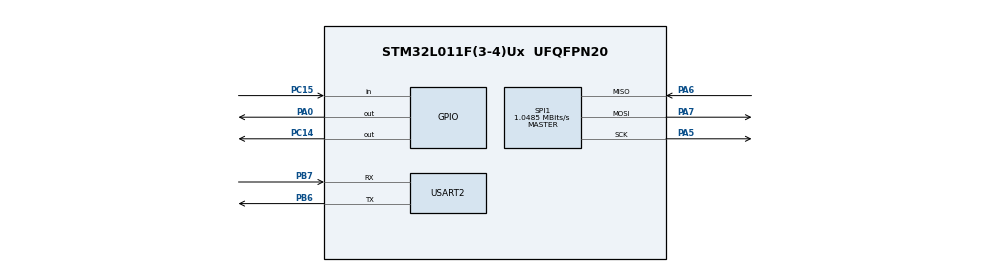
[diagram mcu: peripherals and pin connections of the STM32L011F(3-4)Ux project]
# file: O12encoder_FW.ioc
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Dma.Request0=USART2_TX
Dma.USART2_TX.0.Direction=DMA_MEMORY_TO_PERIPH
Dma.USART2_TX.0.Instance=DMA1_Channel2
Dma.USART2_TX.0.MemDataAlignment=DMA_MDATAALIGN_BYTE
Dma.USART2_TX.0.MemInc=DMA_MINC_ENABLE
Dma.USART2_TX.0.Mode=DMA_NORMAL
Dma.USART2_TX.0.PeriphDataAlignment=DMA_PDATAALIGN_BYTE
Dma.USART2_TX.0.PeriphInc=DMA_PINC_DISABLE
Dma.USART2_TX.0.Priority=DMA_PRIORITY_LOW
Mcu.Family=STM32L0
Mcu.Name=STM32L011F(3-4)Ux
Mcu.Package=UFQFPN20
NVIC.DMA1_Channel2_3_IRQn=true\:0\:0\:false\:false\:true\:false\:true\:true
NVIC.USART2_IRQn=true\:0\:0\:false\:false\:true\:true\:true\:true
PA0-CK_IN.Signal=GPIO_Output
PA13.Mode=Serial_Wire
PA13.Signal=SYS_SWDIO
PA14.Mode=Serial_Wire
PA14.Signal=SYS_SWCLK
PA5.Mode=Full_Duplex_Master
PA5.Signal=SPI1_SCK
PA6.Mode=Full_Duplex_Master
PA6.Signal=SPI1_MISO
PA7.Mode=Full_Duplex_Master
PA7.Signal=SPI1_MOSI
PB6.GPIO_PuPd=GPIO_PULLUP
PB6.Mode=Asynchronous
PB6.Signal=USART2_TX
PB7.GPIO_PuPd=GPIO_PULLUP
PB7.Mode=Asynchronous
PB7.Signal=USART2_RX
PC14-OSC32_IN.Signal=GPIO_Output
PC15-OSC32_OUT.Signal=GPIO_Input
ProjectManager.HeapSize=0x200
ProjectManager.StackSize=0x400
ProjectManager.TargetToolchain=STM32CubeIDE
RCC.AHBFreq_Value=2097000
RCC.APB1Freq_Value=2097000
RCC.APB1TimFreq_Value=2097000
RCC.APB2Freq_Value=2097000
RCC.APB2TimFreq_Value=2097000
RCC.HSE_VALUE=8000000
RCC.HSI16_VALUE=16000000
RCC.HSI_VALUE=16000000
RCC.LSE_VALUE=32768
RCC.MSI_VALUE=2097000
RCC.SYSCLKFreq_VALUE=2097000
RCC.VCOOutputFreq_Value=48000000
SPI1.CalculateBaudRate=1.0485 MBits/s
SPI1.Direction=SPI_DIRECTION_2LINES
SPI1.Mode=SPI_MODE_MASTER
SPI1.VirtualType=VM_MASTER
USART2.VirtualMode-Asynchronous=VM_ASYNC
board=custom

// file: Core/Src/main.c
/* USER CODE BEGIN Header */
/**
 ******************************************************************************
 * @file           : main.c
 * @brief          : Main program body
 ******************************************************************************
 * @attention
 *
 * Copyright (c) 2024 STMicroelectronics.
 * All rights reserved.
 *
 * This software is licensed under terms that can be found in the LICENSE file
 * in the root directory of this software component.
 * If no LICENSE file comes with this software, it is provided AS-IS.
 *
 ******************************************************************************
 */
/* USER CODE END Header */
#include "main.h"

/* USER CODE BEGIN Includes */

#include "comdef.h"
#include "utils.h"

/* USER CODE END Includes */

/* USER CODE BEGIN PD */

#define UART_TX_SIZE 10
#define UART_RX_SIZE 3

/* USER CODE END PD */

SPI_HandleTypeDef hspi1;

UART_HandleTypeDef huart2;
DMA_HandleTypeDef hdma_usart2_tx;

void SystemClock_Config(void);
static void MX_GPIO_Init(void);
static void MX_DMA_Init(void);
static void MX_USART2_UART_Init(void);
static void MX_SPI1_Init(void);

/* USER CODE BEGIN 0 */
static uint8_t uart_TX[UART_TX_SIZE] = {0};
static uint8_t uart_RX[UART_RX_SIZE] = {0};
static uint8_t uart_received_flag = 0;

/* USER CODE END 0 */

int main(void) {

    /* MCU Configuration--------------------------------------------------------*/

    /* Reset of all peripherals, Initializes the Flash interface and the Systick. */
    HAL_Init();

    /* Configure the system clock */
    SystemClock_Config();

    /* Initialize all configured peripherals */
    MX_GPIO_Init();
    MX_DMA_Init();
    MX_USART2_UART_Init();
    MX_SPI1_Init();
    /* USER CODE BEGIN 2 */

    static uint8_t spi_TX[2] = {0};
    static uint8_t spi_RX[2] = {0};

    static uint16_t m_angle = 0;
    static uint16_t m_angle_prev;
    static int32_t revs = 0;
    static int32_t cont_angle = 0;

    static int16_t encoder_res = 7;

    static uint16_t uart_cmd[3] = {0};

    HAL_GPIO_WritePin(GPIOA, GPIO_PIN_0, 1);

    /* USER CODE END 2 */

    /* Infinite loop */
    /* USER CODE BEGIN WHILE */
    while (1) {

        HAL_GPIO_WritePin(GPIOA, GPIO_PIN_0, 0);
        HAL_SPI_TransmitReceive(&hspi1, spi_TX, spi_RX, 2, HAL_MAX_DELAY);
        HAL_GPIO_WritePin(GPIOA, GPIO_PIN_0, 1);

        // angles represented in [0,32767] (~91 per degree)
        m_angle = ((uint16_t)(spi_RX[0]) << 8) + spi_RX[1] + 16384;

        if (m_angle_prev < 8192 && m_angle > 24576) { // detect angle wraparound and increment a revolution
            revs -= 32768;
        } else if (m_angle < 8192 && m_angle_prev > 24576) {
            revs += 32768;
        }
        cont_angle = m_angle + revs;
        m_angle_prev = m_angle;

        HAL_Delay(10);

        // if (uart_received_flag) {
        if (1) {
            uart_received_flag = 0;

            uart_cmd[0] = uart_RX[0] & CMD_MASK;
            uart_cmd[1] = (uart_RX[1] << 7) | (uart_RX[2]);
            uart_cmd[1] = pad14(uart_cmd[1]);

            if (uart_cmd[0] == CMD_GET_POSITION) {
                encoder_res = uart_cmd[1];
            }

            uart_TX[0] = (uint8_t)(cont_angle >> (encoder_res + 7)) & 0b01111111;
            uart_TX[1] = (uint8_t)(cont_angle >> (encoder_res + 0)) & 0b01111111;
            uart_TX[2] = MIN_INT8;

            HAL_GPIO_WritePin(GPIOC, GPIO_PIN_14, 1); // enable TX
            HAL_UART_Transmit_DMA(&huart2, uart_TX, 3);
        }

        /* USER CODE END WHILE */

    }
}

void SystemClock_Config(void) {
    RCC_OscInitTypeDef RCC_OscInitStruct = {0};
    RCC_ClkInitTypeDef RCC_ClkInitStruct = {0};
    RCC_PeriphCLKInitTypeDef PeriphClkInit = {0};

    /** Configure the main internal regulator output voltage
     */
    __HAL_PWR_VOLTAGESCALING_CONFIG(PWR_REGULATOR_VOLTAGE_SCALE1);

    /** Initializes the RCC Oscillators according to the specified parameters
     * in the RCC_OscInitTypeDef structure.
     */
    RCC_OscInitStruct.OscillatorType = RCC_OSCILLATORTYPE_HSI;
    RCC_OscInitStruct.HSIState = RCC_HSI_ON;
    RCC_OscInitStruct.HSICalibrationValue = RCC_HSICALIBRATION_DEFAULT;
    RCC_OscInitStruct.PLL.PLLState = RCC_PLL_ON;
    RCC_OscInitStruct.PLL.PLLSource = RCC_PLLSOURCE_HSI;
    RCC_OscInitStruct.PLL.PLLMUL = RCC_PLLMUL_4;
    RCC_OscInitStruct.PLL.PLLDIV = RCC_PLLDIV_2;
    if (HAL_RCC_OscConfig(&RCC_OscInitStruct) != HAL_OK) {
        Error_Handler();
    }

    /** Initializes the CPU, AHB and APB buses clocks
     */
    RCC_ClkInitStruct.ClockType = RCC_CLOCKTYPE_HCLK | RCC_CLOCKTYPE_SYSCLK | RCC_CLOCKTYPE_PCLK1 | RCC_CLOCKTYPE_PCLK2;
    RCC_ClkInitStruct.SYSCLKSource = RCC_SYSCLKSOURCE_PLLCLK;
    RCC_ClkInitStruct.AHBCLKDivider = RCC_SYSCLK_DIV1;
    RCC_ClkInitStruct.APB1CLKDivider = RCC_HCLK_DIV1;
    RCC_ClkInitStruct.APB2CLKDivider = RCC_HCLK_DIV1;

    if (HAL_RCC_ClockConfig(&RCC_ClkInitStruct, FLASH_LATENCY_1) != HAL_OK) {
        Error_Handler();
    }
    PeriphClkInit.PeriphClockSelection = RCC_PERIPHCLK_USART2;
    PeriphClkInit.Usart2ClockSelection = RCC_USART2CLKSOURCE_SYSCLK;
    if (HAL_RCCEx_PeriphCLKConfig(&PeriphClkInit) != HAL_OK) {
        Error_Handler();
    }
}

static void MX_SPI1_Init(void) {

    /* SPI1 parameter configuration*/
    hspi1.Instance = SPI1;
    hspi1.Init.Mode = SPI_MODE_MASTER;
    hspi1.Init.Direction = SPI_DIRECTION_2LINES;
    hspi1.Init.DataSize = SPI_DATASIZE_8BIT;
    hspi1.Init.CLKPolarity = SPI_POLARITY_LOW;
    hspi1.Init.CLKPhase = SPI_PHASE_1EDGE;
    hspi1.Init.NSS = SPI_NSS_SOFT;
    hspi1.Init.BaudRatePrescaler = SPI_BAUDRATEPRESCALER_2;
    hspi1.Init.FirstBit = SPI_FIRSTBIT_MSB;
    hspi1.Init.TIMode = SPI_TIMODE_DISABLE;
    hspi1.Init.CRCCalculation = SPI_CRCCALCULATION_DISABLE;
    hspi1.Init.CRCPolynomial = 7;
    if (HAL_SPI_Init(&hspi1) != HAL_OK) {
        Error_Handler();
    }
}

static void MX_USART2_UART_Init(void) {

    huart2.Instance = USART2;
    huart2.Init.BaudRate = 115200;
    huart2.Init.WordLength = UART_WORDLENGTH_8B;
    huart2.Init.StopBits = UART_STOPBITS_1;
    huart2.Init.Parity = UART_PARITY_NONE;
    huart2.Init.Mode = UART_MODE_TX_RX;
    huart2.Init.HwFlowCtl = UART_HWCONTROL_NONE;
    huart2.Init.OverSampling = UART_OVERSAMPLING_16;
    huart2.Init.OneBitSampling = UART_ONE_BIT_SAMPLE_DISABLE;
    huart2.AdvancedInit.AdvFeatureInit = UART_ADVFEATURE_NO_INIT;
    if (HAL_UART_Init(&huart2) != HAL_OK) {
        Error_Handler();
    }
}

static void MX_DMA_Init(void) {

    /* DMA controller clock enable */
    __HAL_RCC_DMA1_CLK_ENABLE();

    /* DMA interrupt init */
    /* DMA1_Channel2_3_IRQn interrupt configuration */
    HAL_NVIC_SetPriority(DMA1_Channel2_3_IRQn, 0, 0);
    HAL_NVIC_EnableIRQ(DMA1_Channel2_3_IRQn);
}

static void MX_GPIO_Init(void) {
    GPIO_InitTypeDef GPIO_InitStruct = {0};

    /* GPIO Ports Clock Enable */
    __HAL_RCC_GPIOC_CLK_ENABLE();
    __HAL_RCC_GPIOA_CLK_ENABLE();
    __HAL_RCC_GPIOB_CLK_ENABLE();

    /*Configure GPIO pin Output Level */
    HAL_GPIO_WritePin(GPIOC, GPIO_PIN_14, GPIO_PIN_RESET);

    /*Configure GPIO pin Output Level */
    HAL_GPIO_WritePin(GPIOA, GPIO_PIN_0, GPIO_PIN_RESET);

    /*Configure GPIO pin : PC14 */
    GPIO_InitStruct.Pin = GPIO_PIN_14;
    GPIO_InitStruct.Mode = GPIO_MODE_OUTPUT_PP;
    GPIO_InitStruct.Pull = GPIO_NOPULL;
    GPIO_InitStruct.Speed = GPIO_SPEED_FREQ_LOW;
    HAL_GPIO_Init(GPIOC, &GPIO_InitStruct);

    /*Configure GPIO pin : PC15 */
    GPIO_InitStruct.Pin = GPIO_PIN_15;
    GPIO_InitStruct.Mode = GPIO_MODE_INPUT;
    GPIO_InitStruct.Pull = GPIO_NOPULL;
    HAL_GPIO_Init(GPIOC, &GPIO_InitStruct);

    /*Configure GPIO pin : PA0 */
    GPIO_InitStruct.Pin = GPIO_PIN_0;
    GPIO_InitStruct.Mode = GPIO_MODE_OUTPUT_PP;
    GPIO_InitStruct.Pull = GPIO_NOPULL;
    GPIO_InitStruct.Speed = GPIO_SPEED_FREQ_LOW;
    HAL_GPIO_Init(GPIOA, &GPIO_InitStruct);

}

/* USER CODE BEGIN 4 */

void HAL_UARTEx_RxEventCallback(UART_HandleTypeDef *huart, uint16_t Size) {
    uart_received_flag = 1; // commutation loop will read and clear
}

void HAL_UART_TxCpltCallback(UART_HandleTypeDef *huart) {
    HAL_GPIO_WritePin(GPIOC, GPIO_PIN_14, 0); // set RX
    HAL_UARTEx_ReceiveToIdle_IT(&huart2, uart_RX, UART_RX_SIZE);
}

void HAL_UART_ErrorCallback(UART_HandleTypeDef *huart) { // shouldn't happen but just in case of overrun, restart RX
    // clear the uart buffer
    uint8_t temp_buffer[20];
    while (__HAL_UART_GET_FLAG(&huart2, UART_FLAG_RXNE)) {
        HAL_UART_Receive(&huart2, temp_buffer, 1, 1);
    }

    HAL_GPIO_WritePin(GPIOC, GPIO_PIN_14, 0); // set RX
    HAL_UARTEx_ReceiveToIdle_IT(&huart2, uart_RX, UART_RX_SIZE);
}

/* USER CODE END 4 */

void Error_Handler(void) {
    __disable_irq();
    while (1) {
    }
}
